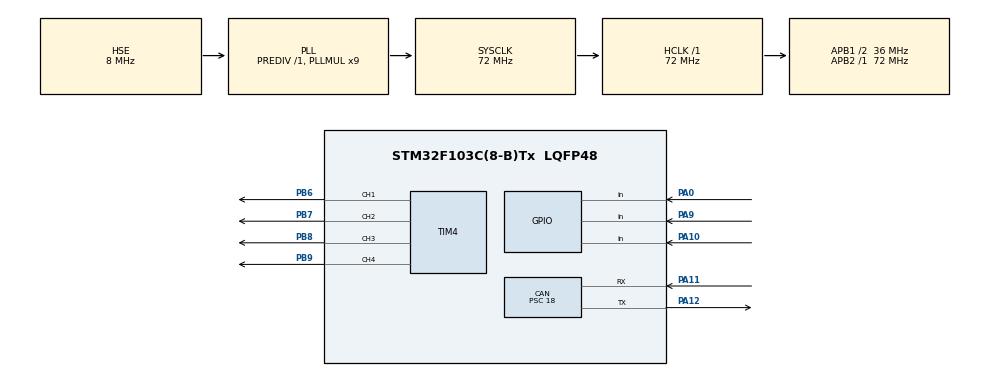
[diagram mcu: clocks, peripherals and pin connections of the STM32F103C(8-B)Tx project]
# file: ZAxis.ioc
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CAN.ABOM=ENABLE
CAN.AWUM=ENABLE
CAN.BS1=CAN_BS1_13TQ
CAN.BS2=CAN_BS2_2TQ
CAN.CalculateTimeBit=1500
CAN.CalculateTimeQuantum=500.0
CAN.NART=ENABLE
CAN.Prescaler=18
FREERTOS.Tasks01=defaultTask,0,128,StartDefaultTask,Default,NULL
Mcu.Family=STM32F1
Mcu.Name=STM32F103C(8-B)Tx
Mcu.Package=LQFP48
Mcu.UserConstants=PWM_FREQUENCY,6000
NVIC.CAN1_RX1_IRQn=true\:5\:0\:false\:false\:true\:true\:true
NVIC.CAN1_SCE_IRQn=true\:5\:0\:false\:false\:true\:true\:true
NVIC.PriorityGroup=NVIC_PRIORITYGROUP_4
NVIC.TIM2_IRQn=true\:0\:0\:false\:false\:true\:false\:false
NVIC.TimeBase=TIM2_IRQn
NVIC.TimeBaseIP=TIM2
NVIC.USB_HP_CAN1_TX_IRQn=true\:5\:0\:false\:false\:true\:true\:true
NVIC.USB_LP_CAN1_RX0_IRQn=true\:5\:0\:false\:false\:true\:true\:true
PA0-WKUP.Signal=GPIO_Input
PA10.Signal=GPIO_Input
PA11.Mode=Master
PA11.Signal=CAN_RX
PA12.Mode=Master
PA12.Signal=CAN_TX
PA13.Mode=Serial_Wire
PA13.Signal=SYS_JTMS-SWDIO
PA14.Mode=Serial_Wire
PA14.Signal=SYS_JTCK-SWCLK
PA9.Signal=GPIO_Input
PB6.Signal=S_TIM4_CH1
PB7.Signal=S_TIM4_CH2
PB8.Signal=S_TIM4_CH3
PB9.Signal=S_TIM4_CH4
PD0-OSC_IN.Mode=HSE-External-Oscillator
PD0-OSC_IN.Signal=RCC_OSC_IN
PD1-OSC_OUT.Mode=HSE-External-Oscillator
PD1-OSC_OUT.Signal=RCC_OSC_OUT
ProjectManager.HeapSize=0x200
ProjectManager.StackSize=0x400
ProjectManager.TargetToolchain=EWARM
RCC.AHBFreq_Value=72000000
RCC.APB1CLKDivider=RCC_HCLK_DIV2
RCC.APB1Freq_Value=36000000
RCC.APB1TimFreq_Value=72000000
RCC.APB2Freq_Value=72000000
RCC.APB2TimFreq_Value=72000000
RCC.HCLKFreq_Value=72000000
RCC.PLLMUL=RCC_PLL_MUL9
RCC.PLLSourceVirtual=RCC_PLLSOURCE_HSE
RCC.SYSCLKFreq_VALUE=72000000
RCC.SYSCLKSource=RCC_SYSCLKSOURCE_PLLCLK
RCC.USBFreq_Value=72000000
SH.S_TIM4_CH1.0=TIM4_CH1,PWM Generation1 CH1
SH.S_TIM4_CH2.0=TIM4_CH2,PWM Generation2 CH2
SH.S_TIM4_CH3.0=TIM4_CH3,PWM Generation3 CH3
SH.S_TIM4_CH4.0=TIM4_CH4,PWM Generation4 CH4
TIM4.Channel-PWM\ Generation1\ CH1=TIM_CHANNEL_1
TIM4.Channel-PWM\ Generation2\ CH2=TIM_CHANNEL_2
TIM4.Channel-PWM\ Generation3\ CH3=TIM_CHANNEL_3
TIM4.Channel-PWM\ Generation4\ CH4=TIM_CHANNEL_4
TIM4.Period=72000000/PWM_FREQUENCY-1
VP_FREERTOS_VS_ENABLE.Mode=Enabled
VP_SYS_VS_tim2.Mode=TIM2
board=custom

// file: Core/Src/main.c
/**
  ******************************************************************************
  * @file           : main.c
  * @brief          : Main program body
  ******************************************************************************
  * This notice applies to any and all portions of this file
  * that are not between comment pairs USER CODE BEGIN and
  * USER CODE END. Other portions of this file, whether
  * inserted by the user or by software development tools
  * are owned by their respective copyright owners.
  *
  * Copyright (c) 2018 STMicroelectronics International N.V.
  * All rights reserved.
  *
  * Redistribution and use in source and binary forms, with or without
  * modification, are permitted, provided that the following conditions are met:
  *
  * 1. Redistribution of source code must retain the above copyright notice,
  *    this list of conditions and the following disclaimer.
  * 2. Redistributions in binary form must reproduce the above copyright notice,
  *    this list of conditions and the following disclaimer in the documentation
  *    and/or other materials provided with the distribution.
  * 3. Neither the name of STMicroelectronics nor the names of other
  *    contributors to this software may be used to endorse or promote products
  *    derived from this software without specific written permission.
  * 4. This software, including modifications and/or derivative works of this
  *    software, must execute solely and exclusively on microcontroller or
  *    microprocessor devices manufactured by or for STMicroelectronics.
  * 5. Redistribution and use of this software other than as permitted under
  *    this license is void and will automatically terminate your rights under
  *    this license.
  *
  * THIS SOFTWARE IS PROVIDED BY STMICROELECTRONICS AND CONTRIBUTORS "AS IS"
  * AND ANY EXPRESS, IMPLIED OR STATUTORY WARRANTIES, INCLUDING, BUT NOT
  * LIMITED TO, THE IMPLIED WARRANTIES OF MERCHANTABILITY, FITNESS FOR A
  * PARTICULAR PURPOSE AND NON-INFRINGEMENT OF THIRD PARTY INTELLECTUAL PROPERTY
  * RIGHTS ARE DISCLAIMED TO THE FULLEST EXTENT PERMITTED BY LAW. IN NO EVENT
  * SHALL STMICROELECTRONICS OR CONTRIBUTORS BE LIABLE FOR ANY DIRECT, INDIRECT,
  * INCIDENTAL, SPECIAL, EXEMPLARY, OR CONSEQUENTIAL DAMAGES (INCLUDING, BUT NOT
  * LIMITED TO, PROCUREMENT OF SUBSTITUTE GOODS OR SERVICES; LOSS OF USE, DATA,
  * OR PROFITS; OR BUSINESS INTERRUPTION) HOWEVER CAUSED AND ON ANY THEORY OF
  * LIABILITY, WHETHER IN CONTRACT, STRICT LIABILITY, OR TORT (INCLUDING
  * NEGLIGENCE OR OTHERWISE) ARISING IN ANY WAY OUT OF THE USE OF THIS SOFTWARE,
  * EVEN IF ADVISED OF THE POSSIBILITY OF SUCH DAMAGE.
  *
  ******************************************************************************
  */
#include "main.h"
#include "stm32f1xx_hal.h"
#include "cmsis_os.h"

/* USER CODE BEGIN Includes */
#include "zaxis.h"
#include "test.h"
/* USER CODE END Includes */

CAN_HandleTypeDef hcan;

TIM_HandleTypeDef htim4;

osThreadId defaultTaskHandle;

/* USER CODE BEGIN PV */
/* Private variables ---------------------------------------------------------*/
osThreadId PeriodicityTaskHandle;
/* USER CODE END PV */

void SystemClock_Config(void);
static void MX_GPIO_Init(void);
static void MX_CAN_Init(void);
static void MX_TIM4_Init(void);
void StartDefaultTask(void const * argument);

void HAL_TIM_MspPostInit(TIM_HandleTypeDef *htim);

/* USER CODE BEGIN PFP */
/* Private function prototypes -----------------------------------------------*/
void PeriodicityTask(void const * argument);
static void CAN_Filter_Init(void);
/* USER CODE END PFP */

int main(void)
{

  /* MCU Configuration----------------------------------------------------------*/

  /* Reset of all peripherals, Initializes the Flash interface and the Systick. */
  HAL_Init();

  /* Configure the system clock */
  SystemClock_Config();

  /* Initialize all configured peripherals */
  MX_GPIO_Init();
  MX_CAN_Init();
  MX_TIM4_Init();
  /* USER CODE BEGIN 2 */
  CAN_Filter_Init();
  HAL_CAN_Receive_IT(&hcan, CAN_FIFO0);
	HAL_TIM_PWM_Start(&htim4,TIM_CHANNEL_3);
	HAL_TIM_PWM_Start(&htim4,TIM_CHANNEL_4);
  ZAxis_Init();
  /* USER CODE END 2 */

  /* Create the thread(s) */
  /* definition and creation of defaultTask */
  osThreadDef(defaultTask, StartDefaultTask, osPriorityNormal, 0, 128);
  defaultTaskHandle = osThreadCreate(osThread(defaultTask), NULL);

  /* USER CODE BEGIN RTOS_THREADS */
  /* add threads, ... */
  osThreadDef(task1, PeriodicityTask, osPriorityRealtime, 0, 256);
  PeriodicityTaskHandle = osThreadCreate(osThread(task1), NULL);
  /* USER CODE END RTOS_THREADS */

  /* Start scheduler */
  osKernelStart();

  /* We should never get here as control is now taken by the scheduler */

  /* Infinite loop */
  while (1)
  {

  }

}

void SystemClock_Config(void)
{

  RCC_OscInitTypeDef RCC_OscInitStruct;
  RCC_ClkInitTypeDef RCC_ClkInitStruct;

    /**Initializes the CPU, AHB and APB busses clocks
    */
  RCC_OscInitStruct.OscillatorType = RCC_OSCILLATORTYPE_HSE;
  RCC_OscInitStruct.HSEState = RCC_HSE_ON;
  RCC_OscInitStruct.HSEPredivValue = RCC_HSE_PREDIV_DIV1;
  RCC_OscInitStruct.HSIState = RCC_HSI_ON;
  RCC_OscInitStruct.PLL.PLLState = RCC_PLL_ON;
  RCC_OscInitStruct.PLL.PLLSource = RCC_PLLSOURCE_HSE;
  RCC_OscInitStruct.PLL.PLLMUL = RCC_PLL_MUL9;
  if (HAL_RCC_OscConfig(&RCC_OscInitStruct) != HAL_OK)
  {
    _Error_Handler(__FILE__, __LINE__);
  }

    /**Initializes the CPU, AHB and APB busses clocks
    */
  RCC_ClkInitStruct.ClockType = RCC_CLOCKTYPE_HCLK|RCC_CLOCKTYPE_SYSCLK
                              |RCC_CLOCKTYPE_PCLK1|RCC_CLOCKTYPE_PCLK2;
  RCC_ClkInitStruct.SYSCLKSource = RCC_SYSCLKSOURCE_PLLCLK;
  RCC_ClkInitStruct.AHBCLKDivider = RCC_SYSCLK_DIV1;
  RCC_ClkInitStruct.APB1CLKDivider = RCC_HCLK_DIV2;
  RCC_ClkInitStruct.APB2CLKDivider = RCC_HCLK_DIV1;

  if (HAL_RCC_ClockConfig(&RCC_ClkInitStruct, FLASH_LATENCY_2) != HAL_OK)
  {
    _Error_Handler(__FILE__, __LINE__);
  }

    /**Configure the Systick interrupt time
    */
  HAL_SYSTICK_Config(HAL_RCC_GetHCLKFreq()/1000);

    /**Configure the Systick
    */
  HAL_SYSTICK_CLKSourceConfig(SYSTICK_CLKSOURCE_HCLK);

  /* SysTick_IRQn interrupt configuration */
  HAL_NVIC_SetPriority(SysTick_IRQn, 15, 0);
}

/* CAN init function */
static void MX_CAN_Init(void)
{

  hcan.Instance = CAN1;
  hcan.Init.Prescaler = 18;
  hcan.Init.Mode = CAN_MODE_NORMAL;
  hcan.Init.SJW = CAN_SJW_1TQ;
  hcan.Init.BS1 = CAN_BS1_13TQ;
  hcan.Init.BS2 = CAN_BS2_2TQ;
  hcan.Init.TTCM = DISABLE;
  hcan.Init.ABOM = ENABLE;
  hcan.Init.AWUM = ENABLE;
  hcan.Init.NART = ENABLE;
  hcan.Init.RFLM = DISABLE;
  hcan.Init.TXFP = DISABLE;
  if (HAL_CAN_Init(&hcan) != HAL_OK)
  {
    _Error_Handler(__FILE__, __LINE__);
  }

}

/* TIM4 init function */
static void MX_TIM4_Init(void)
{

  TIM_MasterConfigTypeDef sMasterConfig;
  TIM_OC_InitTypeDef sConfigOC;

  htim4.Instance = TIM4;
  htim4.Init.Prescaler = 0;
  htim4.Init.CounterMode = TIM_COUNTERMODE_UP;
  htim4.Init.Period = 72000000/PWM_FREQUENCY-1;
  htim4.Init.ClockDivision = TIM_CLOCKDIVISION_DIV1;
  htim4.Init.AutoReloadPreload = TIM_AUTORELOAD_PRELOAD_DISABLE;
  if (HAL_TIM_PWM_Init(&htim4) != HAL_OK)
  {
    _Error_Handler(__FILE__, __LINE__);
  }

  sMasterConfig.MasterOutputTrigger = TIM_TRGO_RESET;
  sMasterConfig.MasterSlaveMode = TIM_MASTERSLAVEMODE_DISABLE;
  if (HAL_TIMEx_MasterConfigSynchronization(&htim4, &sMasterConfig) != HAL_OK)
  {
    _Error_Handler(__FILE__, __LINE__);
  }

  sConfigOC.OCMode = TIM_OCMODE_PWM1;
  sConfigOC.Pulse = 0;
  sConfigOC.OCPolarity = TIM_OCPOLARITY_HIGH;
  sConfigOC.OCFastMode = TIM_OCFAST_DISABLE;
  if (HAL_TIM_PWM_ConfigChannel(&htim4, &sConfigOC, TIM_CHANNEL_3) != HAL_OK)
  {
    _Error_Handler(__FILE__, __LINE__);
  }

  if (HAL_TIM_PWM_ConfigChannel(&htim4, &sConfigOC, TIM_CHANNEL_4) != HAL_OK)
  {
    _Error_Handler(__FILE__, __LINE__);
  }

  HAL_TIM_MspPostInit(&htim4);

}

/** Configure pins as
        * Analog
        * Input
        * Output
        * EVENT_OUT
        * EXTI
*/
static void MX_GPIO_Init(void)
{

  GPIO_InitTypeDef GPIO_InitStruct;

  /* GPIO Ports Clock Enable */
  __HAL_RCC_GPIOC_CLK_ENABLE();
  __HAL_RCC_GPIOD_CLK_ENABLE();
  __HAL_RCC_GPIOA_CLK_ENABLE();
  __HAL_RCC_GPIOB_CLK_ENABLE();

  /*Configure GPIO pin Output Level */
  HAL_GPIO_WritePin(GPIOC, GPIO_PIN_13, GPIO_PIN_RESET);

  /*Configure GPIO pin Output Level */
  HAL_GPIO_WritePin(GPIOA, GPIO_PIN_7, GPIO_PIN_RESET);

  /*Configure GPIO pin Output Level */
  HAL_GPIO_WritePin(GPIOB, STEP_MOTOR_DIR_Pin|STEP_MOTOR_ENABLE_Pin|GPIO_PIN_5|GPIO_PIN_6
                          |GPIO_PIN_7, GPIO_PIN_RESET);

  /*Configure GPIO pin : PC13 */
  GPIO_InitStruct.Pin = GPIO_PIN_13;
  GPIO_InitStruct.Mode = GPIO_MODE_OUTPUT_PP;
  GPIO_InitStruct.Pull = GPIO_NOPULL;
  GPIO_InitStruct.Speed = GPIO_SPEED_FREQ_LOW;
  HAL_GPIO_Init(GPIOC, &GPIO_InitStruct);

  /*Configure GPIO pin : PA0 */
  GPIO_InitStruct.Pin = GPIO_PIN_0;
  GPIO_InitStruct.Mode = GPIO_MODE_INPUT;
  GPIO_InitStruct.Pull = GPIO_NOPULL;
  HAL_GPIO_Init(GPIOA, &GPIO_InitStruct);

  /*Configure GPIO pin : PA7 */
  GPIO_InitStruct.Pin = GPIO_PIN_7;
  GPIO_InitStruct.Mode = GPIO_MODE_OUTPUT_PP;
  GPIO_InitStruct.Pull = GPIO_NOPULL;
  GPIO_InitStruct.Speed = GPIO_SPEED_FREQ_LOW;
  HAL_GPIO_Init(GPIOA, &GPIO_InitStruct);

  /*Configure GPIO pins : PB0 PB1 */
  GPIO_InitStruct.Pin = GPIO_PIN_0|GPIO_PIN_1;
  GPIO_InitStruct.Mode = GPIO_MODE_INPUT;
  GPIO_InitStruct.Pull = GPIO_NOPULL;
  HAL_GPIO_Init(GPIOB, &GPIO_InitStruct);

  /*Configure GPIO pins : STEP_MOTOR_DIR_Pin STEP_MOTOR_ENABLE_Pin */
  GPIO_InitStruct.Pin = STEP_MOTOR_DIR_Pin|STEP_MOTOR_ENABLE_Pin;
  GPIO_InitStruct.Mode = GPIO_MODE_OUTPUT_PP;
  GPIO_InitStruct.Pull = GPIO_NOPULL;
  GPIO_InitStruct.Speed = GPIO_SPEED_FREQ_LOW;
  HAL_GPIO_Init(GPIOB, &GPIO_InitStruct);

  /*Configure GPIO pin : PA8 */
  GPIO_InitStruct.Pin = GPIO_PIN_8;
  GPIO_InitStruct.Mode = GPIO_MODE_INPUT;
  GPIO_InitStruct.Pull = GPIO_PULLUP;
  HAL_GPIO_Init(GPIOA, &GPIO_InitStruct);

  /*Configure GPIO pins : PB5 PB6 PB7 */
  GPIO_InitStruct.Pin = GPIO_PIN_5|GPIO_PIN_6|GPIO_PIN_7;
  GPIO_InitStruct.Mode = GPIO_MODE_OUTPUT_PP;
  GPIO_InitStruct.Pull = GPIO_PULLDOWN;
  GPIO_InitStruct.Speed = GPIO_SPEED_FREQ_LOW;
  HAL_GPIO_Init(GPIOB, &GPIO_InitStruct);

}

/* USER CODE BEGIN 4 */
CanTxMsgTypeDef txmsg;
CanRxMsgTypeDef rxmsg;
static void CAN_Filter_Init(void)
{
  hcan.pTxMsg = &txmsg;
  hcan.pTxMsg->ExtId = 2;
  hcan.pTxMsg->DLC = 8;
  hcan.pTxMsg->IDE = CAN_ID_EXT;
  hcan.pTxMsg->RTR = CAN_RTR_DATA;

  hcan.pRxMsg = &rxmsg;
  hcan.pRxMsg->ExtId = 1;
  hcan.pRxMsg->DLC = 8;
  hcan.pRxMsg->IDE = CAN_ID_EXT;
  hcan.pRxMsg->RTR = CAN_RTR_DATA;

  CAN_FilterConfTypeDef  sFilterConfig;

  sFilterConfig.FilterNumber = 0;                       //使用过滤器0
  sFilterConfig.FilterMode = CAN_FILTERMODE_IDMASK;     //掩码模式
  sFilterConfig.FilterScale = CAN_FILTERSCALE_32BIT;    //配置为32位宽
  sFilterConfig.FilterIdHigh = 0;
  sFilterConfig.FilterIdLow = 0|CAN_ID_STD;             //设置IDE位为0
  sFilterConfig.FilterMaskIdHigh = 0x00;
  sFilterConfig.FilterMaskIdLow = 0x00;                 //全部为0，所有的ID都能通过，不过滤
  sFilterConfig.FilterFIFOAssignment = 0;               //接收到的报文放入到FIFO0中
  sFilterConfig.FilterActivation = ENABLE;
  sFilterConfig.BankNumber = 14;

  HAL_CAN_ConfigFilter(&hcan, &sFilterConfig);

  return;
}

void PeriodicityTask(void const * argument)
{
    static TickType_t xLastWakeTime;
    const TickType_t xTimeIncrement = pdMS_TO_TICKS(1);

    xLastWakeTime = xTaskGetTickCount();
    for(;;)
    {
        vTaskDelayUntil(&xLastWakeTime,xTimeIncrement);

        SwitchScan();
        UpdateDistance(&ZAxis);
        HeartBeat();
        //osDelay(1);
    }
}
/* USER CODE END 4 */

/* StartDefaultTask function */
void StartDefaultTask(void const * argument)
{

  /* USER CODE BEGIN 5 */
  HAL_Delay(1500);
  //ResetZaxis();
  /* Infinite loop */
  for(;;)
  {
    ZAxisMain();
//    Test_MoveStable();
  }
  /* USER CODE END 5 */
}

void HAL_TIM_PeriodElapsedCallback(TIM_HandleTypeDef *htim)
{
  if (htim->Instance == TIM2) {
    HAL_IncTick();
  }
}

void _Error_Handler(char *file, int line)
{
  while(1)
  {
  }
}

/************************ (C) COPYRIGHT STMicroelectronics *****END OF FILE****/
